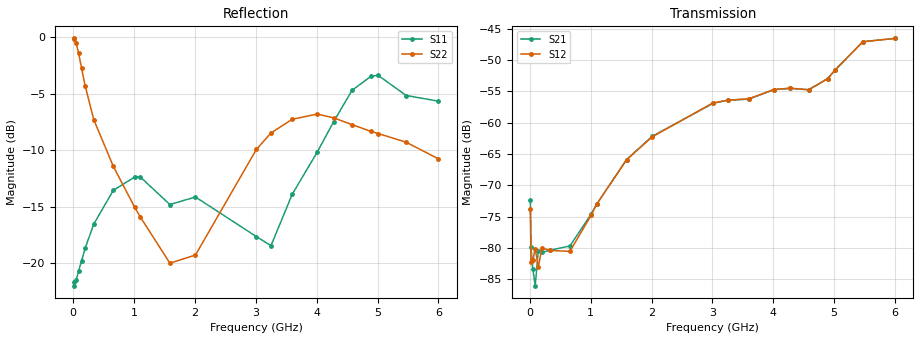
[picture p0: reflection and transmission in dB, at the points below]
!Agilent Technologies,N5230A,MY45001650,A.07.50.48
!Agilent N5230A: A.07.50.48
!Date: Saturday, July 08, 2017 15:46:25
!Correction: S11(Full 2 Port(1,2))
!S21(Full 2 Port(1,2))
!S12(Full 2 Port(1,2))
!S22(Full 2 Port(1,2))
!S2P File: Measurements: S11, S21, S12, S22:
# Hz S  dB  R 50
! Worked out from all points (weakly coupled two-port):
!   600 points, 10 MHz to 6 GHz, reference 50 ohm
!   highest |S21| = -46.56 dB at 6 GHz (marker M1); lowest = -86.0 dB at 90 MHz (marker M2)
!   lowest |S11| = -22.0 dB at 20 MHz (marker M3), VSWR 1.17, Z = 58.6 - j1.27 ohm
!   |S11| at or under -10 dB: start of sweep to 4.026 GHz
!   |S22| runs from -20.6 to -0.1 dB; largest |S21 - S12| = 0.00023
!   S11 on the Smith chart (normalised r, x): 10 MHz: 1.18, -0.02; 1.1 GHz: 0.61, +0.00; 4.28 GHz: 0.99, +0.93; 4.89 GHz: 2.77, +2.43; 6 GHz: 2.72, -1.05
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1e7  -21.68 -6.3  -72.40 167.3  -73.70 104.6  -0.11 -5.7
2e7  -21.97 -7.8  -79.75 116.2  -82.21 -23.1  -0.15 -11.0
5e7  -21.47 -17.2  -83.31 67.0  -81.93 42.9  -0.50 -26.5
9e7  -20.69 -31.7  -85.99 71.1  -80.10 84.0  -1.39 -44.8
1.4e8  -19.78 -46.4  -80.48 35.3  -83.05 40.7  -2.76 -63.4
2e8  -18.63 -61.7  -80.67 -11.5  -79.98 -7.0  -4.34 -80.9
3.4e8  -16.52 -92.9  -80.32 -43.9  -80.37 -48.9  -7.30 -108.9
6.6e8  -13.55 -137.8  -79.66 -142.6  -80.52 -143.5  -11.41 -145.4
1.01e9  -12.37 -171.2  -74.55 144.3  -74.72 145.3  -15.02 -165.4
1.1e9  -12.34 179.4  -73.00 129.7  -72.98 128.5  -15.86 -170.1
1.59e9  -14.80 160.2  -65.88 65.5  -65.92 66.1  -19.98 -179.8
2.01e9  -14.13 157.4  -62.18 15.7  -62.27 15.4  -19.26 -174.6
3.01e9  -17.63 149.9  -56.93 -91.3  -56.84 -91.5  -9.93 152.6
3.25e9  -18.43 160.3  -56.42 -118.6  -56.43 -118.9  -8.47 144.4
3.6e9  -13.88 142.1  -56.25 -151.1  -56.17 -150.6  -7.26 133.4
4.01e9  -10.16 88.4  -54.72 172.3  -54.72 172.3  -6.80 119.1
4.28e9  -7.47 65.7  -54.54 145.2  -54.49 145.2  -7.14 108.3
4.58e9  -4.71 43.2  -54.75 126.2  -54.76 126.4  -7.73 94.5
4.89e9  -3.47 21.1  -53.00 114.2  -53.02 114.6  -8.33 76.2
5.01e9  -3.38 13.9  -51.67 107.2  -51.65 107.3  -8.52 69.3
5.47e9  -5.16 -4.4  -47.09 57.1  -47.10 57.2  -9.29 40.5
6e9  -5.66 -15.7  -46.56 6.6  -46.57 6.8  -10.76 9.6
